One B-rep face of a CAD part: STEP entity #541.
In plain terms, the planar face has unit normal (1, 0, 0).
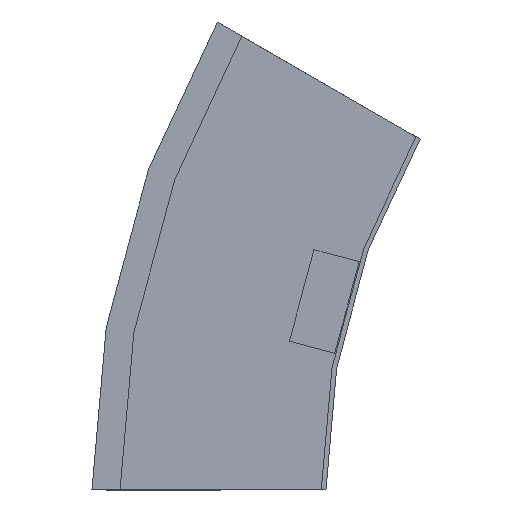
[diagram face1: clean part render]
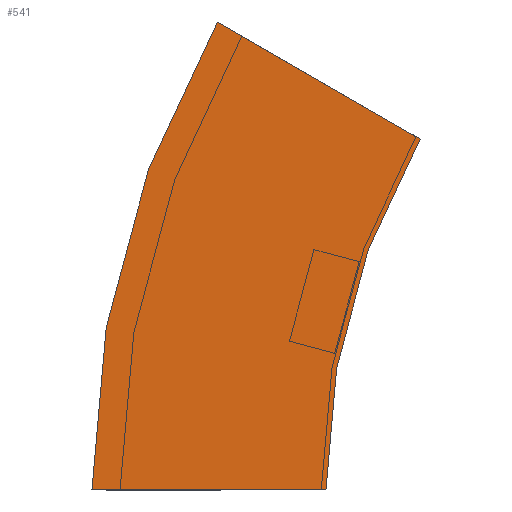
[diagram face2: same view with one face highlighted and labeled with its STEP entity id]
Its self-contained STEP definition (entity closure, numbers rounded to 3 decimals):
#18 = DIRECTION ( 'NONE',  ( 0., 0.866, 0.5 ) ) ;
#38 = CARTESIAN_POINT ( 'NONE',  ( 0., 100., 0. ) ) ;
#40 = DIRECTION ( 'NONE',  ( 0., 1., 0. ) ) ;
#48 = EDGE_CURVE ( 'NONE', #99, #239, #218, .T. ) ;
#65 = VECTOR ( 'NONE', #358, 1000. ) ;
#81 = CIRCLE ( 'NONE', #168, 300. ) ;
#91 = AXIS2_PLACEMENT_3D ( 'NONE', #273, #379, #337 ) ;
#92 = EDGE_CURVE ( 'NONE', #239, #126, #350, .T. ) ;
#99 = VERTEX_POINT ( 'NONE', #542 ) ;
#107 = PLANE ( 'NONE',  #91 ) ;
#116 = DIRECTION ( 'NONE',  ( 1., 0., 0. ) ) ;
#126 = VERTEX_POINT ( 'NONE', #172 ) ;
#153 = DIRECTION ( 'NONE',  ( 0., 1., 0. ) ) ;
#168 = AXIS2_PLACEMENT_3D ( 'NONE', #474, #210, #40 ) ;
#172 = CARTESIAN_POINT ( 'NONE',  ( 0., 46.41, 200. ) ) ;
#192 = LINE ( 'NONE', #329, #434 ) ;
#210 = DIRECTION ( 'NONE',  ( 1., 0., 0. ) ) ;
#214 = ORIENTED_EDGE ( 'NONE', *, *, #282, .F. ) ;
#218 = LINE ( 'NONE', #257, #65 ) ;
#239 = VERTEX_POINT ( 'NONE', #38 ) ;
#257 = CARTESIAN_POINT ( 'NONE',  ( 0., 0., 0. ) ) ;
#273 = CARTESIAN_POINT ( 'NONE',  ( 0., 0., 0. ) ) ;
#282 = EDGE_CURVE ( 'NONE', #99, #357, #81, .T. ) ;
#287 = AXIS2_PLACEMENT_3D ( 'NONE', #555, #116, #153 ) ;
#329 = CARTESIAN_POINT ( 'NONE',  ( 0., -40.192, 150. ) ) ;
#337 = DIRECTION ( 'NONE',  ( 0., 0., -1. ) ) ;
#350 = CIRCLE ( 'NONE', #287, 400. ) ;
#357 = VERTEX_POINT ( 'NONE', #437 ) ;
#358 = DIRECTION ( 'NONE',  ( 0., 1., 0. ) ) ;
#379 = DIRECTION ( 'NONE',  ( 1., 0., 0. ) ) ;
#393 = EDGE_LOOP ( 'NONE', ( #395, #399, #214, #456 ) ) ;
#395 = ORIENTED_EDGE ( 'NONE', *, *, #92, .T. ) ;
#399 = ORIENTED_EDGE ( 'NONE', *, *, #449, .F. ) ;
#434 = VECTOR ( 'NONE', #18, 1000. ) ;
#437 = CARTESIAN_POINT ( 'NONE',  ( 0., -40.192, 150. ) ) ;
#449 = EDGE_CURVE ( 'NONE', #357, #126, #192, .T. ) ;
#456 = ORIENTED_EDGE ( 'NONE', *, *, #48, .T. ) ;
#474 = CARTESIAN_POINT ( 'NONE',  ( 0., -300., 0. ) ) ;
#540 = FACE_OUTER_BOUND ( 'NONE', #393, .T. ) ;
#541 = ADVANCED_FACE ( 'NONE', ( #540 ), #107, .T. ) ;
#542 = CARTESIAN_POINT ( 'NONE',  ( 0., 0., 0. ) ) ;
#555 = CARTESIAN_POINT ( 'NONE',  ( 0., -300., 0. ) ) ;
